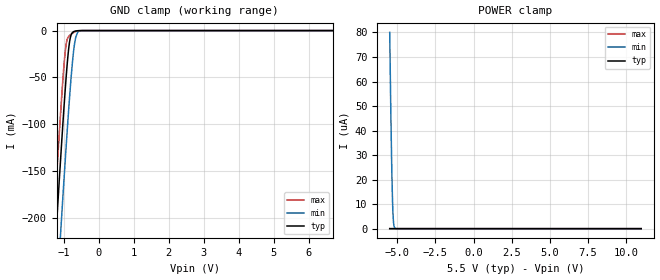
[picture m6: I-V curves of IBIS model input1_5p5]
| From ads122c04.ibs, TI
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|   input1_5p5 Model
[Model]   input1_5p5
Model_type   Input
Vinl = 1.65
Vinh = 3.85
|   typ   min   max
C_comp   6.04837E-13   5.61864E-13   6.42144E-13
[Model spec]
|subparameter
Vinl   1.65   1.6497   1.6503
Vinh   3.85   3.8493   3.8507
| Where Nom  PVT is Nominal Process, 5.5V, 27C
|   Fast PVT is Strong Process,  5.501V, -40C
|   Slow PVT is Weak Process,   5.499, 125C
[Voltage Range]   5.5   5.499   5.501
[Temperature Range]   27   125   -40
[Power Clamp Reference]   5.5   5.499   5.501
[GND Clamp Reference]   0   0   0
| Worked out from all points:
|   GND clamp passes 1 mA (typ) near -0.70 V on its own axis
[GND Clamp]
|   Voltage   I(typ)   I(min)   I(max)
-5.5V     -3.028A    -3.1A      -2.983A
-1.375V   -316.7mA   -396.8mA   -266.2mA
-1.243V   -234mA     -314.2mA   -183.5mA
-1.194V   -203.5mA   -283.5mA   -153mA
-1.111V   -153.4mA   -233mA     -103.7mA
-1.045V   -114.6mA   -193.3mA   -66.35mA
-946mV    -60.14mA   -135.5mA   -20.73mA
-830.5mV  -12.75mA   -72.77mA   -5.353mA
-682mV    -700.8uA   -13.19mA   -1.431mA
-599.5mV  -146.1uA   -2.018mA   -345.4uA
-451mV    -3.533uA   -35uA      -5.167uA
11V       0A         0A         0A
[POWER Clamp]
|   Voltage   I(typ)   I(min)   I(max)
-5.5V     8.516nA    80.03uA    5.63nA
-5.45V    0A         57.6uA     0A
-5.401V   0A         37.29uA    0A
-5.368V   0A         25.54uA    0A
-5.351V   0A         20.39uA    0A
-5.319V   0A         11.89uA    0A
-5.302V   0A         8.636uA    0A
-5.285V   0A         6.064uA    0A
-5.253V   0A         2.731uA    0A
-5.22V    0A         1.126uA    0A
-5.154V   0A         166.3nA    0A
11V       0A         0A         0A
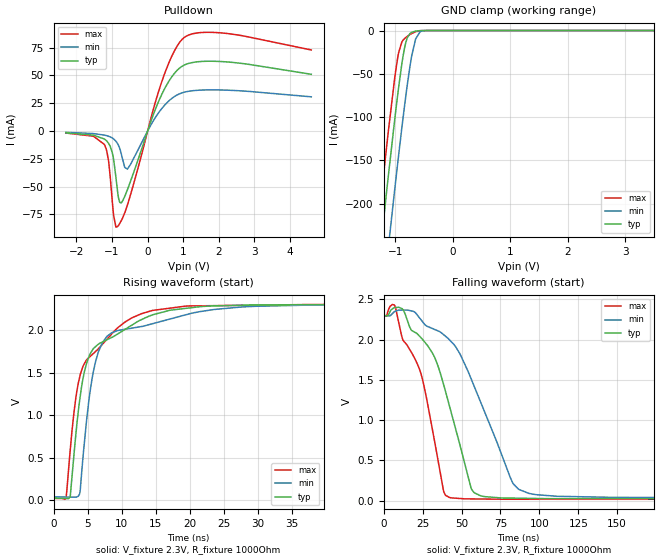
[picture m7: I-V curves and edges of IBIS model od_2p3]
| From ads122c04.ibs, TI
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|   od_2p3 Model
[Model]   od_2p3
Model_type   I/O_open_drain
Polarity   Non-Inverting
Enable   Active-Low
Vinl = 0.69
Vinh = 1.61
Vmeas = 1.15
Vref = 2.3
Cref = 2pF
Rref = 1000
|   typ   min   max
C_comp   1.18476E-12   1.14193E-12   1.2236E-12
|C_comp_pulldown   1.20125E-12   1.13675E-12   1.25787E-12
[Model spec]
|subparameter
Vinl   0.69   0.6897   0.6903
Vinh   1.61   1.6093   1.6107
| Where Nom  PVT is Nominal Process, 2.3V, 27C
|   Fast PVT is Strong Process,  2.301V, -40C
|   Slow PVT is Weak Process,   2.299, 125C
[Voltage Range]   2.3   2.299   2.301
[Temperature Range]   27   125   -40
[Pullup Reference]   2.3   2.299   2.301
[Pulldown Reference]   -0   -0   -0
[Power Clamp Reference]   2.3   2.299   2.301
[GND Clamp Reference]   0   0   0
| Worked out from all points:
|   slope of the pulldown table from 0 to 0.345 V, typ, clamps not added: 11.8 ohm
|   GND clamp passes 1 mA (typ) near -0.66 V on its own axis
|   falling waveform, V_fixture 2.3V, R_fixture 1000Ohm: 20-80 % time 20.9ns typ, 29.1ns min, 17.4ns max; typ from 2.3 V to 0.023 V
|   rising waveform, V_fixture 2.3V, R_fixture 1000Ohm: 20-80 % time 3.86ns typ, 2.84ns min, 4.99ns max; typ from 0.023 V to 2.3 V
[Pulldown]
|   Voltage   I(typ)   I(min)   I(max)
-2.3V     -1.644mA   -1.178mA   -1.8mA
-1.217V   -7.185mA   -3.66mA    -12.06mA
-1.099V   -10.96mA   -4.706mA   -26.58mA
-995.9mV  -19.17mA   -6.246mA   -62.4mA
-885.5mV  -43.35mA   -9.363mA   -86.41mA
-782mV    -64.15mA   -15.91mA   -82.95mA
-568.1mV  -52.8mA    -34.21mA   -66.59mA
349.6mV   29.6mA     18.23mA    39.72mA
687.7mV   49.11mA    29.51mA    67.82mA
977.5mV   58.4mA     34.42mA    82.65mA
2.04V     62.5mA     36.91mA    88.27mA
4.6V      50.99mA    30.74mA    72.85mA
[GND Clamp]
|   Voltage   I(typ)   I(min)   I(max)
-2.3V     -925.1mA   -1.006A    -874.7mA
-1.375V   -326.9mA   -410.1mA   -274.5mA
-1.161V   -193.6mA   -276.5mA   -141.5mA
-1.12V    -168.4mA   -251.1mA   -116.8mA
-1.01V    -103.6mA   -184.6mA   -55.46mA
-940.7mV  -65.89mA   -144.3mA   -25.68mA
-885.5mV  -39.01mA   -113.1mA   -13.4mA
-816.5mV  -14.06mA   -76.21mA   -8.123mA
-713mV    -2.054mA   -29.33mA   -3.464mA
-644mV    -627.8uA   -9.555mA   -1.373mA
-492.2mV  -18.73uA   -216uA     -33.52uA
4.6V      0A         0A         0A
[POWER Clamp]
|   Voltage   I(typ)   I(min)   I(max)
-2.3V     0A         0A         0A
0V        0A         0A         0A
4.6V      0A         0A         0A
[Ramp]
R_load = 1000
|   typ   min   max
dV/dt_r   1.36595/3.85796e-09   1.3571/2.83456e-09   1.36988/4.98481e-09
dV/dt_f   1.36595/2.08603e-08   1.3571/2.91306e-08   1.36988/1.74232e-08
[Falling Waveform]
V_fixture = 2.3V
V_fixture_min = 2.299V
V_fixture_max = 2.301V
R_fixture = 1000Ohm
C_fixture = 0F
|   Time   V(typ)   V(min)   V(max)
0s        2.3V       2.299V     2.301V
6.794ns   2.397V     2.347V     2.431V
12.2ns    2.375V     2.367V     2.003V
22.82ns   2.047V     2.275V     1.642V
32.67ns   1.782V     2.127V     739.9mV
38.39ns   1.448V     2.063V     125.7mV
42.11ns   1.185V     2V         41.85mV
58.06ns   100.5mV    1.424V     22.72mV
86.74ns   31.87mV    141.5mV    18.94mV
240ns     23.42mV    37.16mV    17.87mV
[Rising Waveform]
V_fixture = 2.3V
V_fixture_min = 2.299V
V_fixture_max = 2.301V
R_fixture = 1000Ohm
C_fixture = 0F
|   Time   V(typ)   V(min)   V(max)
0s        23.42mV    37.16mV    17.87mV
1.835ns   17.22mV    34.99mV    19.35mV
2.451ns   34.5mV     34.26mV    582.1mV
3.832ns   1.165V     71.19mV    1.44V
5.323ns   1.711V     1.246V     1.684V
6.582ns   1.833V     1.74V      1.778V
7.857ns   1.886V     1.925V     1.892V
14.55ns   2.179V     2.075V     2.231V
29.63ns   2.296V     2.28V      2.293V
120ns     2.3V       2.299V     2.301V
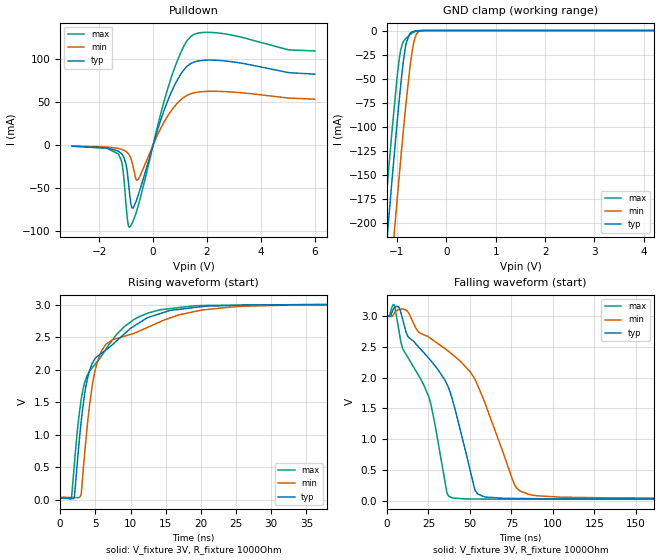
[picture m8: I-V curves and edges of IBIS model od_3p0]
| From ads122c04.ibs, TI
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|   od_3p0 Model
[Model]   od_3p0
Model_type   I/O_open_drain
Polarity   Non-Inverting
Enable   Active-Low
Vinl = 0.9
Vinh = 2.1
Vmeas = 1.5
Vref = 3.0
Cref = 2pF
Rref = 1000
|   typ   min   max
C_comp   1.14719E-12   1.10062E-12   1.17934E-12
|C_comp_pulldown   1.19572E-12   1.14193E-12   1.24061E-12
[Model spec]
|subparameter
Vinl   0.9   0.8997   0.9003
Vinh   2.1   2.0993   2.1007
| Where Nom  PVT is Nominal Process, 3.0V, 27C
|   Fast PVT is Strong Process,  3.001V, -40C
|   Slow PVT is Weak Process,   2.999, 125C
[Voltage Range]   3   2.999   3.001
[Temperature Range]   27   125   -40
[Pullup Reference]   3   2.999   3.001
[Pulldown Reference]   0   0   0
[Power Clamp Reference]   3   2.999   3.001
[GND Clamp Reference]   0   0   0
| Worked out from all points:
|   slope of the pulldown table from 0 to 0.45 V, typ, clamps not added: 10.2 ohm
|   GND clamp passes 1 mA (typ) near -0.67 V on its own axis
|   falling waveform, V_fixture 3V, R_fixture 1000Ohm: 20-80 % time 26.8ns typ, 33.9ns min, 22.1ns max; typ from 3 V to 0.027 V
|   rising waveform, V_fixture 3V, R_fixture 1000Ohm: 20-80 % time 5.16ns typ, 3.33ns min, 5.01ns max; typ from 0.027 V to 3 V
[Pulldown]
|   Voltage   I(typ)   I(min)   I(max)
-3V       -1.28mA    -987.4uA   -1.32mA
-1.281V   -7.191mA   -3.962mA   -10.84mA
-1.119V   -12.27mA   -5.487mA   -28.43mA
-1.011V   -21.68mA   -7.32mA    -66.99mA
-948mV    -34.06mA   -9.027mA   -87.79mA
-867mV    -58.2mA    -12.62mA   -95.56mA
-741mV    -73.3mA    -25.44mA   -88.27mA
-561mV    -59mA      -40.31mA   -71.63mA
528mV     50.56mA    33.22mA    64.14mA
1.023V    82.35mA    52.61mA    107.5mA
1.401V    95.12mA    59.84mA    126.7mA
6V        82.62mA    53.52mA    109.7mA
[GND Clamp]
|   Voltage   I(typ)   I(min)   I(max)
-3V       -1.385A    -1.464A    -1.336A
-1.335V   -301.4mA   -384.6mA   -248.9mA
-1.164V   -195.1mA   -278.1mA   -143mA
-1.101V   -157mA     -239.5mA   -105.6mA
-1.002V   -99.23mA   -180.1mA   -51.63mA
-921mV    -55.84mA   -133mA     -19.92mA
-867mV    -31.11mA   -102.9mA   -11.45mA
-813mV    -13.18mA   -74.42mA   -7.937mA
-687mV    -1.336mA   -20.43mA   -2.561mA
-606mV    -293.1uA   -4.122mA   -674.7uA
-480mV    -13.53uA   -155.7uA   -22.9uA
6V        0A         0A         0A
[POWER Clamp]
|   Voltage   I(typ)   I(min)   I(max)
-3V       0A         0A         0A
0V        0A         0A         0A
6V        0A         0A         0A
[Ramp]
R_load = 1000
|   typ   min   max
dV/dt_r   1.78391/5.18217e-09   1.77556/3.26439e-09   1.78759/4.99856e-09
dV/dt_f   1.78391/2.67359e-08   1.77556/3.39532e-08   1.78759/2.20856e-08
[Falling Waveform]
V_fixture = 3V
V_fixture_min = 2.999V
V_fixture_max = 3.001V
R_fixture = 1000Ohm
C_fixture = 0F
|   Time   V(typ)   V(min)   V(max)
0s        3V         2.999V     3.001V
4.357ns   3.133V     3.043V     3.182V
9.256ns   2.965V     3.115V     2.483V
12.55ns   2.672V     3.069V     2.328V
25.1ns    2.317V     2.66V      1.692V
36.06ns   1.898V     2.448V     135.5mV
39.14ns   1.67V      2.383V     47mV
53.12ns   168.3mV    1.965V     27.05mV
80.42ns   35.11mV    153.6mV    22.8mV
240ns     26.82mV    39.73mV    21.68mV
[Rising Waveform]
V_fixture = 3V
V_fixture_min = 2.999V
V_fixture_max = 3.001V
R_fixture = 1000Ohm
C_fixture = 0F
|   Time   V(typ)   V(min)   V(max)
0s        26.82mV    39.73mV    21.68mV
1.596ns   22.36mV    34.65mV    19.59mV
2.003ns   33.72mV    33.36mV    527.8mV
2.95ns    1.163V     71.36mV    1.514V
3.597ns   1.705V     846mV      1.837V
4.506ns   2.084V     1.709V     2.022V
6.51ns    2.303V     2.39V      2.315V
14.23ns   2.862V     2.736V     2.921V
32.72ns   2.997V     2.992V     2.998V
120ns     3V         2.999V     3.001V
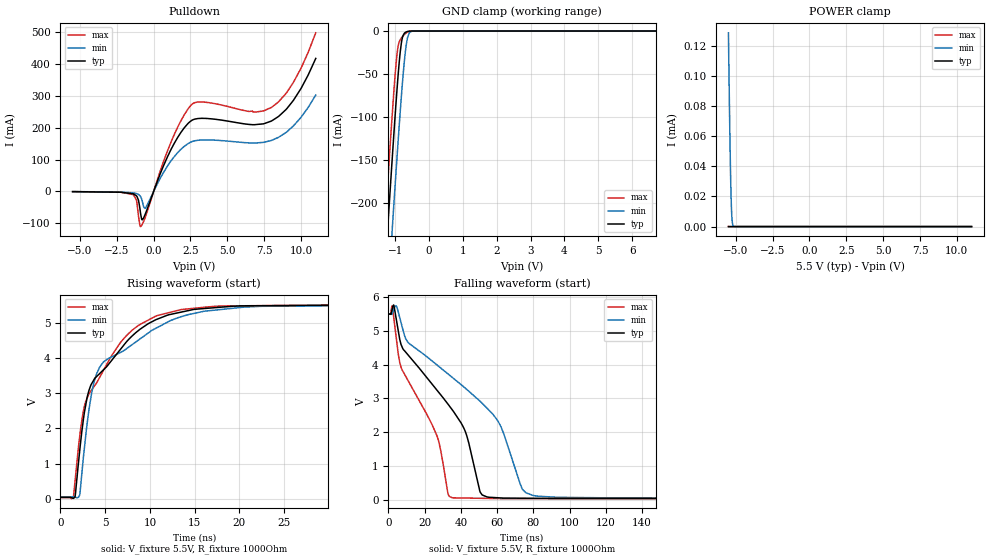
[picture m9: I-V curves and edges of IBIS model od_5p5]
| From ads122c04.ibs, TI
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|   od_5p5 Model
[Model]   od_5p5
Model_type   I/O_open_drain
Polarity   Non-Inverting
Enable   Active-Low
Vinl = 1.65
Vinh = 3.85
Vmeas = 2.75
Vref = 5.5
Cref = 2pF
Rref = 1000
|   typ   min   max
C_comp   1.04626E-12   1.00379E-12   1.08051E-12
|C_comp_pulldown   1.14193E-12   1.11594E-12   1.16316E-12
[Model spec]
|subparameter
Vinl   1.65   1.6497   1.6503
Vinh   3.85   3.8493   3.8507
| Where Nom  PVT is Nominal Process, 5.5V, 27C
|   Fast PVT is Strong Process,  5.501V, -40C
|   Slow PVT is Weak Process,   5.499, 125C
[Voltage Range]   5.5   5.499   5.501
[Temperature Range]   27   125   -40
[Pullup Reference]   5.5   5.499   5.501
[Pulldown Reference]   -0   0   0
[Power Clamp Reference]   5.5   5.499   5.501
[GND Clamp Reference]   0   0   0
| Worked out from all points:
|   slope of the pulldown table from 0 to 0.825 V, typ, clamps not added: 8.53 ohm
|   GND clamp passes 1 mA (typ) near -0.67 V on its own axis
|   falling waveform, V_fixture 5.5V, R_fixture 1000Ohm: 20-80 % time 37.8ns typ, 51.8ns min, 24.7ns max; typ from 5.5 V to 0.042 V
|   rising waveform, V_fixture 5.5V, R_fixture 1000Ohm: 20-80 % time 5.17ns typ, 5.65ns min, 4.76ns max; typ from 0.042 V to 5.5 V
[Pulldown]
|   Voltage   I(typ)   I(min)   I(max)
-5.5V     -741.5uA   -641.7uA   -704.1uA
-1.375V   -7.601mA   -4.686mA   -10.1mA
-1.177V   -13.35mA   -6.695mA   -26.05mA
-1.028V   -27.91mA   -9.758mA   -77.31mA
-880mV    -71.36mA   -17.07mA   -110.3mA
-764.5mV  -89.1mA    -31.92mA   -102.3mA
-566.5mV  -70.81mA   -52.62mA   -80.95mA
1.117V    125.7mA    91.66mA    147.7mA
2.552V    221.7mA    155.2mA    271mA
7.964V    220.1mA    159.4mA    262.6mA
9.482V    285.4mA    205.2mA    341.8mA
11V       416.9mA    302mA      497.2mA
[GND Clamp]
|   Voltage   I(typ)   I(min)   I(max)
-5.5V     -3.038A    -3.113A    -2.991A
-1.359V   -316.2mA   -399.4mA   -263.8mA
-1.226V   -233.6mA   -316.7mA   -181.2mA
-1.095V   -153.1mA   -235.5mA   -101.9mA
-995.5mV  -95.58mA   -176.2mA   -48.46mA
-929.5mV  -60.12mA   -137.9mA   -22.21mA
-814mV    -13.43mA   -74.93mA   -7.99mA
-731.5mV  -2.806mA   -36.55mA   -4.179mA
-665.5mV  -926.5uA   -14.35mA   -1.916mA
-583mV    -176.6uA   -2.341mA   -405.4uA
-451mV    -6.088uA   -71.06uA   -8.878uA
11V       0A         0A         0A
[POWER Clamp]
|   Voltage   I(typ)   I(min)   I(max)
-5.5V     1.477nA    128.6uA    9.65nA
-5.45V    0A         92.49uA    0A
-5.401V   0A         59.88uA    0A
-5.368V   0A         41.01uA    0A
-5.351V   0A         32.73uA    0A
-5.319V   0A         19.07uA    0A
-5.302V   0A         13.85uA    0A
-5.285V   0A         9.714uA    0A
-5.253V   0A         4.358uA    0A
-5.22V    0A         1.78uA     0A
-5.154V   0A         237.2nA    0A
11V       0A         0A         0A
[Ramp]
R_load = 1000
|   typ   min   max
dV/dt_r   3.27489/5.15508e-09   3.26602/5.65336e-09   3.27871/4.76181e-09
dV/dt_f   3.27489/3.78347e-08   3.26602/5.15755e-08   3.27871/2.47704e-08
[Falling Waveform]
V_fixture = 5.5V
V_fixture_min = 5.499V
V_fixture_max = 5.501V
R_fixture = 1000Ohm
C_fixture = 0F
|   Time   V(typ)   V(min)   V(max)
0s        5.5V       5.499V     5.501V
2.117ns   5.65V      5.505V     5.743V
6.937ns   4.606V     5.256V     3.932V
26.64ns   3.257V     3.999V     1.919V
35.23ns   2.665V     3.624V     66.11mV
42.65ns   1.994V     3.295V     55.86mV
51.78ns   147mV      2.858V     47.59mV
73.79ns   50.59mV    333.6mV    37.6mV
79.81ns   48.19mV    133mV      37.58mV
240ns     41.86mV    55.63mV    36.48mV
[Rising Waveform]
V_fixture = 5.5V
V_fixture_min = 5.499V
V_fixture_max = 5.501V
R_fixture = 1000Ohm
C_fixture = 0F
|   Time   V(typ)   V(min)   V(max)
0s        41.86mV    55.63mV    36.48mV
1.431ns   15.11mV    55.97mV    30.85mV
1.661ns   106.1mV    44.66mV    577.1mV
2.136ns   1.325V     97.1mV     1.737V
3.199ns   3.085V     2.553V     2.986V
4.381ns   3.554V     3.736V     3.446V
8.001ns   4.618V     4.373V     4.781V
13.48ns   5.296V     5.167V     5.369V
22.43ns   5.478V     5.462V     5.481V
120ns     5.5V       5.499V     5.501V
